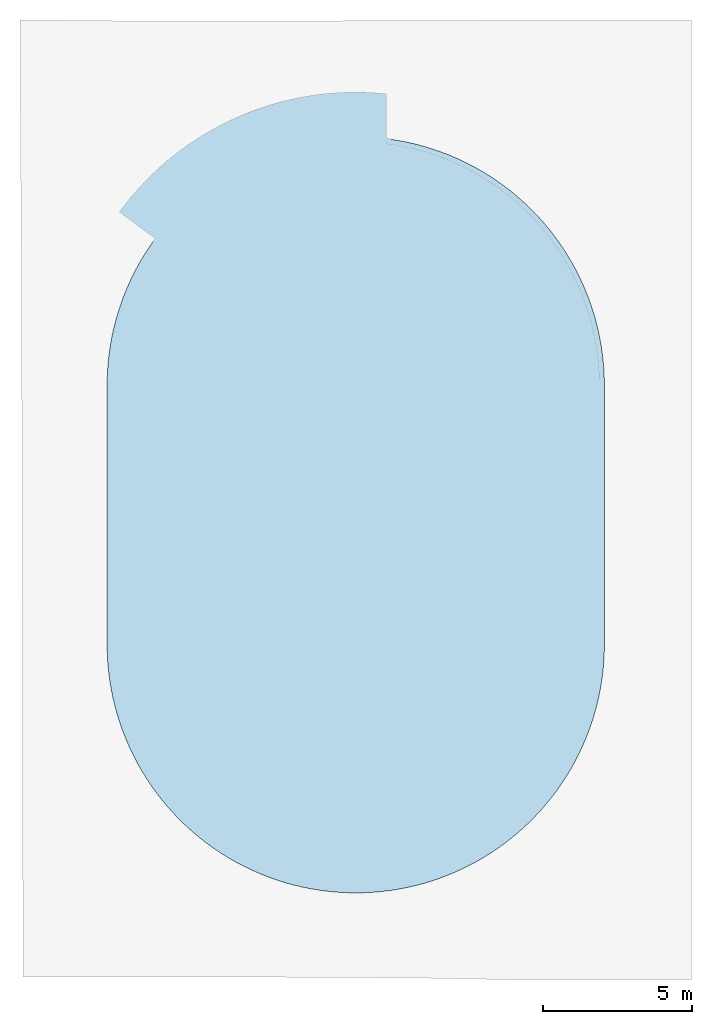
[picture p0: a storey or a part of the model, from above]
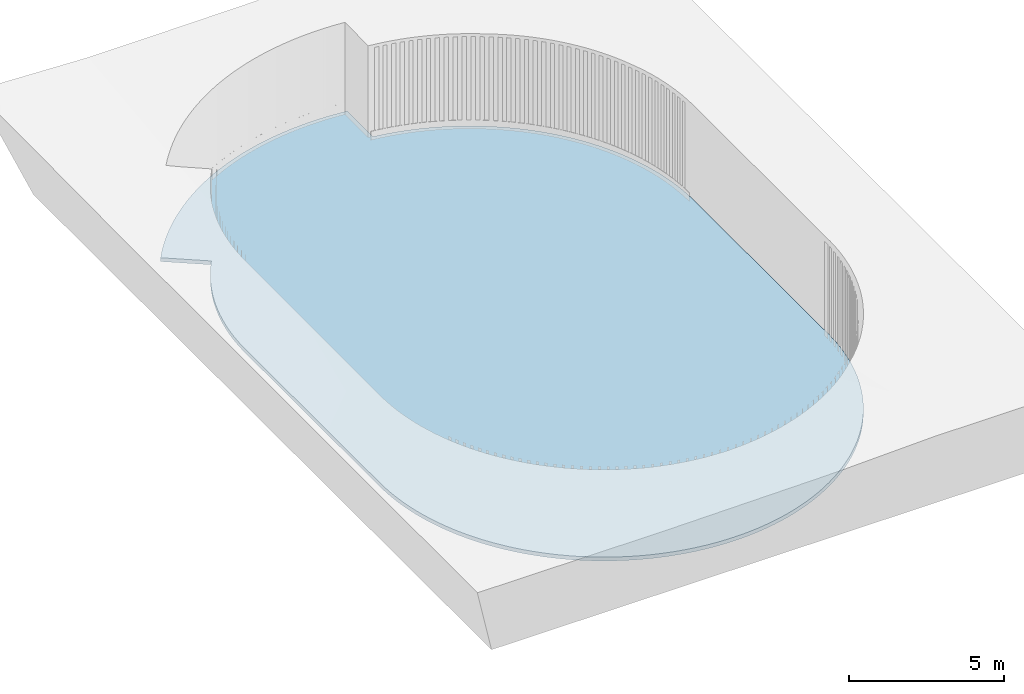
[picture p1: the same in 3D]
Properties of the parts of a building model (IFC4)

# File
Description: ViewDefinition [Design_Transfer_View, QuantityTakeOffAddOnView, SpaceBoundary2ndLevelAddOnView], ExchangeRequirement [Architecture], Option [Elements to export: Visible elements (on all stories)], Option [Partial Structure Display: Entire Model], Option [IFC Domain: All], Option [Structural Function: All Elements], Option [Convert Grid elements: On], Option [Convert IFC Annotations and Archicad 2D elements: Off], Option [Convert 2D symbols of Doors and Windows: Off], Option [Export geometries that Participates in Collision Detection only: Off], Option [Split complex elements: Off], Option [Material Preservation: Explode where necessary], Option [Elements in Solid Element Operations: Extruded/revolved], Option [Elements with junctions: Extruded/revolved without junctions], Option [IFC Model position: Survey Point and Project Origin], Option [Curtain Wall export mode: Container Element], Option [Railing export mode: Single Element], Option [Stair export mode: Container Element], Option [Properties To Export: All properties], Option [Space containment: On], Option [IFC Domain For Space Containment: All], Option [Geometry to type objects: Off], Option [Element Properties: Off], Option [Building Material Properties: Off], Option [Element Parameters: Off], Option [Component Parameters: Off], Option [IFC Base Quantities: On], Option [Door Window Parameters: On], Option [IFC Space boundaries: On], Option [Archicad Zone Categories as IFC Space classification data: Off], Option [Element Classifications: Off]
File name: C:\Users\micel\OneDrive\Dokumenty\ŠKOLA\!!4.LS!!\BAKALÁŘKA\Publikace\Nová složka\LES24-PST-XX-M3-Teren_zpevnene_plochy.ifc
Time: 2024-05-22T15:32:12
Author: Architect
Organization: Building Designer Office
Written by: DDS_IFC v3.0
Made in: IFC file generated by Graphisoft Archicad 27.0.0 CZE FULL Windows version (IFC add-on version: 3001 CZE FULL).
Authorization: The authorising person

# IfcProject, Univerzitní lezecké centrum
Description: BIM projekt - bakalářská práce

# IfcSite, Exteriér
RefLatitude: 50, 1, 18, 339575; RefLongitude: 15, 46, 11, 568244; RefElevation: 221783 mm
Qto_SiteBaseQuantities - GrossPerimeter: 0 mm; GrossArea: 3562 m2

# IfcBuilding, Univerzitní lezecké centrum
Qto_BuildingBaseQuantities - GrossFloorArea: 0 m2

# IfcBuildingStorey (2)
In: Univerzitní lezecké centrum
Qto_BuildingStoreyBaseQuantities - GrossFloorArea: 0 m2
Name | Elevation (mm) | NetHeight (mm) = GrossHeight (mm)
ZÁKLADY | -4070 | 720
1.NP | 0 | 3200

# IfcBeam: Parkoviště 24 (2)
In: 1.NP
Type - PredefinedType: BEAM
Pset_BeamCommon - Status: EXISTING; LoadBearing: yes
Pset_ManufacturerOccurrence - AcquisitionDate: DD.MM.RRRR

# IfcDiscreteAccessory: !Okapový chodník/Terasa/chodník 312 (2)
In: 1.NP
Material: Zemina - hutněná, Geotextilie 300 g/m2, Štěrk - frakce 8/16, Štěrk - frakce 4/8, Betonová dlažba zámková
Pset_ManufacturerOccurrence - AcquisitionDate: DD.MM.RRRR
Pset_ElementComponentCommon - Status: EXISTING

# IfcSlab: !Okapový chodník/Terasa/chodník 312 (9)
In: 1.NP
Type - PredefinedType: ROOF
Pset_ManufacturerOccurrence - AcquisitionDate: DD.MM.RRRR
Pset_SlabCommon - Status: EXISTING; LoadBearing: yes
Qto_SlabBaseQuantities - Width: 312 mm; Betonová dlažba zámková, Width: 60 mm; Štěrk - frakce 4/8, Width: 40 mm; Štěrk - frakce 8/16, Width: 160 mm; Geotextilie 300 g/m2, Width: 2 mm; Zemina - hutněná, Width: 50 mm
Name | Material | Perimeter (mm) | GrossArea (m2) = NetArea (m2) | GrossVolume (m3) = NetVolume (m3)
 | Betonová dlažba zámková 60 mm, Štěrk - frakce 4/8 40 mm, Štěrk - frakce 8/16 160 mm, Geotextilie 300 g/m2 2 mm, Zemina - hutněná 50 mm | 30022.6 | 50.1368 | 15.6427
 | Betonová dlažba zámková 60 mm, Štěrk - frakce 4/8 40 mm, Štěrk - frakce 8/16 160 mm, Geotextilie 300 g/m2 2 mm, Zemina - hutněná 50 mm | 104986 | 237.463 | 74.0884
 | Betonová dlažba zámková, Štěrk - frakce 4/8, Štěrk - frakce 8/16, Geotextilie 300 g/m2, Zemina - hutněná | 39915.7 | 38.3613 | 11.9687
 | Betonová dlažba zámková, Štěrk - frakce 4/8, Štěrk - frakce 8/16, Geotextilie 300 g/m2, Zemina - hutněná | 42278.4 | 52.2637 | 16.3063
 | Betonová dlažba zámková 60 mm, Štěrk - frakce 4/8 40 mm, Štěrk - frakce 8/16 160 mm, Geotextilie 300 g/m2 2 mm, Zemina - hutněná 50 mm | 11798 | 2.83391 | 0.884179
 | Betonová dlažba zámková, Štěrk - frakce 4/8, Štěrk - frakce 8/16, Geotextilie 300 g/m2, Zemina - hutněná | 17636 | 11.047 | 3.44665
 | Betonová dlažba zámková, Štěrk - frakce 4/8, Štěrk - frakce 8/16, Geotextilie 300 g/m2, Zemina - hutněná | 19110.2 | 12.2268 | 3.81476
 | Betonová dlažba zámková, Štěrk - frakce 4/8, Štěrk - frakce 8/16, Geotextilie 300 g/m2, Zemina - hutněná | 25885.6 | 6.06014 | 1.89076
 | Betonová dlažba zámková, Štěrk - frakce 4/8, Štěrk - frakce 8/16, Geotextilie 300 g/m2, Zemina - hutněná | 21002.5 | 13.3815 | 4.17503

# IfcSlab: !Terasa - dřevěná na zemních vrutech 275
In: 1.NP
Type - PredefinedType: ROOF
Material: Dřevěná prkna - terasová, Dřevo - nosné (2)
Pset_SlabCommon - Status: EXISTING; LoadBearing: yes
Qto_SlabBaseQuantities - Width: 275 mm; Perimeter: 30669 mm; GrossArea: 53.2209 m2; NetArea: 53.2209 m2; GrossVolume: 14.6357 m3; NetVolume: 14.6357 m3; Dřevěná prkna - terasová, Width: 25 mm; Dřevo - nosné 1, Width: 100 mm; Dřevo - nosné 2, Width: 150 mm
Pset_ManufacturerOccurrence - AcquisitionDate: DD.MM.RRRR

# IfcSlab: Beton prostý 250 (11)
In: 1.NP
Type - PredefinedType: ROOF
Pset_SlabCommon - Status: EXISTING; LoadBearing: yes
Qto_SlabBaseQuantities - Width: 250 mm; Beton prostý, Width: 250 mm
Pset_ManufacturerOccurrence - AcquisitionDate: DD.MM.RRRR
Name | Material | Perimeter (mm) | GrossArea (m2) = NetArea (m2) | GrossVolume (m3) = NetVolume (m3)
 | Beton prostý 250 mm | 30926.2 | 2.28296 | 0.570741
 | Beton prostý 250 mm | 106204 | 7.99001 | 1.9975
 | Beton prostý | 15483.6 | 0.612454 | 0.153116
 | Beton prostý | 14576.7 | 0.576829 | 0.144207
 | Beton prostý | 12633.4 | 0.498524 | 0.124631
 | Beton prostý | 43445.1 | 1.73088 | 0.432721
 | Beton prostý | 17405.4 | 0.689501 | 0.172375
 | Beton prostý | 17379 | 0.688078 | 0.172019
 | Beton prostý 250 mm | 16762.3 | 0.663731 | 0.165933
 | Beton prostý | 19238.1 | 0.762967 | 0.190742
 | Beton prostý 250 mm | 25209.9 | 1.16707 | 0.291769

# IfcSlab: Zemina - hutněná 4500
In: ZÁKLADY
Type - PredefinedType: FLOOR
Material: Zemina - hutněná
Pset_SlabCommon - Status: EXISTING; LoadBearing: yes
Pset_ManufacturerOccurrence - AcquisitionDate: DD.MM.RRRR
Qto_SlabBaseQuantities - Width: 4500 mm; Perimeter: 111984 mm; GrossArea: 0 m2; NetArea: 0 m2; GrossVolume: 995.677 m3; NetVolume: 995.677 m3; Zemina - hutněná, Width: 4500 mm

# IfcSlab: Zátěžové kamenivo - frakce 4/16 150
In: ZÁKLADY
Type - PredefinedType: FLOOR
Material: Zátěžové kamenivo - frakce 4/16 150 mm
Pset_SlabCommon - Status: EXISTING; LoadBearing: yes
Pset_ManufacturerOccurrence - AcquisitionDate: DD.MM.RRRR
Qto_SlabBaseQuantities - Width: 150 mm; Perimeter: 74781.2 mm; GrossArea: 381.454 m2; NetArea: 381.454 m2; GrossVolume: 57.2182 m3; NetVolume: 57.2182 m3; Zátěžové kamenivo - frakce 4/16, Width: 150 mm
